VERSION 5.7 ;
BUSBITCHARS "[]" ;
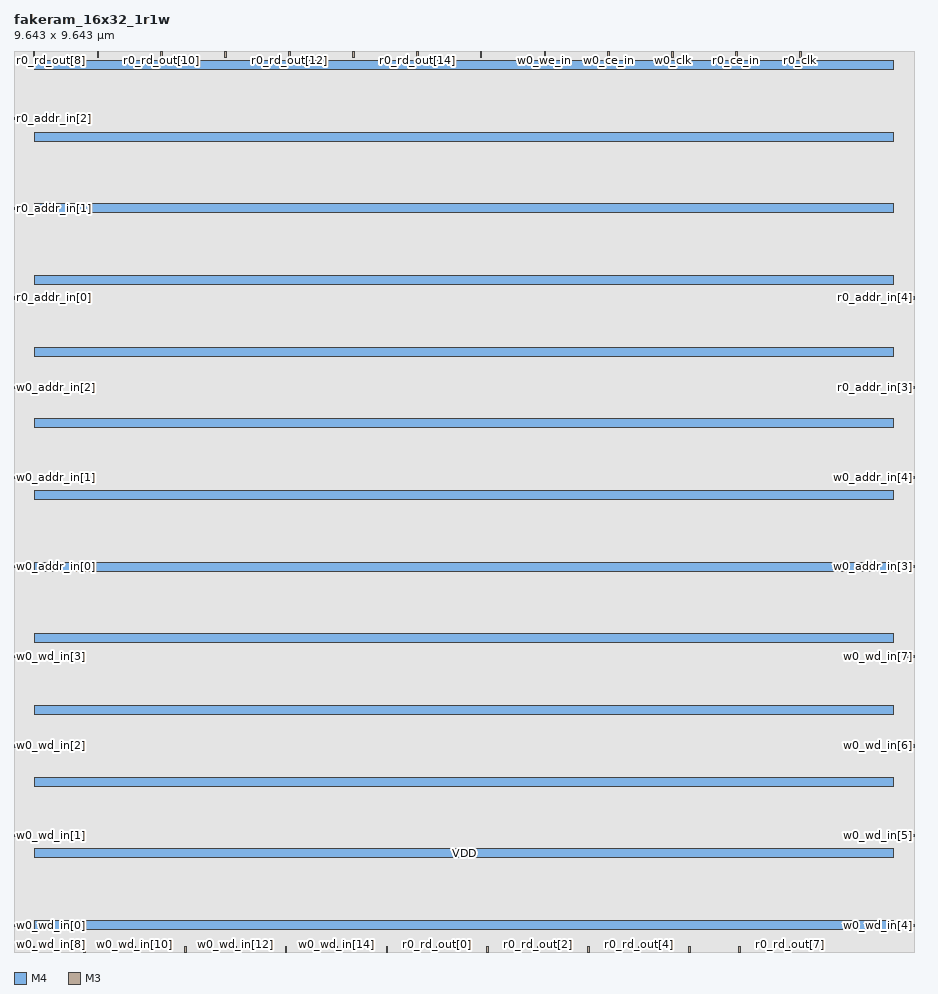
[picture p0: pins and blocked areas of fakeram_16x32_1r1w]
MACRO fakeram_16x32_1r1w
  FOREIGN fakeram_16x32_1r1w 0 0 ;
  SYMMETRY X Y R90 ;
  SIZE 9.643 BY 9.643 ;
  CLASS BLOCK ;
  PIN w0_wd_in[0]
    DIRECTION INPUT ;
    USE SIGNAL ;
    SHAPE ABUTMENT ;
    PORT
      LAYER M4 ;
      RECT 0.000 0.276 0.072 0.300 ;
    END
  END w0_wd_in[0]
  PIN w0_wd_in[1]
    DIRECTION INPUT ;
    USE SIGNAL ;
    SHAPE ABUTMENT ;
    PORT
      LAYER M4 ;
      RECT 0.000 1.236 0.072 1.260 ;
    END
  END w0_wd_in[1]
  PIN w0_wd_in[2]
    DIRECTION INPUT ;
    USE SIGNAL ;
    SHAPE ABUTMENT ;
    PORT
      LAYER M4 ;
      RECT 0.000 2.196 0.072 2.220 ;
    END
  END w0_wd_in[2]
  PIN w0_wd_in[3]
    DIRECTION INPUT ;
    USE SIGNAL ;
    SHAPE ABUTMENT ;
    PORT
      LAYER M4 ;
      RECT 0.000 3.156 0.072 3.180 ;
    END
  END w0_wd_in[3]
  PIN w0_wd_in[4]
    DIRECTION INPUT ;
    USE SIGNAL ;
    SHAPE ABUTMENT ;
    PORT
      LAYER M4 ;
      RECT 9.571 0.276 9.643 0.300 ;
    END
  END w0_wd_in[4]
  PIN w0_wd_in[5]
    DIRECTION INPUT ;
    USE SIGNAL ;
    SHAPE ABUTMENT ;
    PORT
      LAYER M4 ;
      RECT 9.571 1.236 9.643 1.260 ;
    END
  END w0_wd_in[5]
  PIN w0_wd_in[6]
    DIRECTION INPUT ;
    USE SIGNAL ;
    SHAPE ABUTMENT ;
    PORT
      LAYER M4 ;
      RECT 9.571 2.196 9.643 2.220 ;
    END
  END w0_wd_in[6]
  PIN w0_wd_in[7]
    DIRECTION INPUT ;
    USE SIGNAL ;
    SHAPE ABUTMENT ;
    PORT
      LAYER M4 ;
      RECT 9.571 3.156 9.643 3.180 ;
    END
  END w0_wd_in[7]
  PIN w0_wd_in[8]
    DIRECTION OUTPUT ;
    USE SIGNAL ;
    SHAPE ABUTMENT ;
    PORT
      LAYER M3 ;
      RECT 0.207 0.000 0.225 0.054 ;
    END
  END w0_wd_in[8]
  PIN w0_wd_in[9]
    DIRECTION OUTPUT ;
    USE SIGNAL ;
    SHAPE ABUTMENT ;
    PORT
      LAYER M3 ;
      RECT 0.747 0.000 0.765 0.054 ;
    END
  END w0_wd_in[9]
  PIN w0_wd_in[10]
    DIRECTION OUTPUT ;
    USE SIGNAL ;
    SHAPE ABUTMENT ;
    PORT
      LAYER M3 ;
      RECT 1.287 0.000 1.305 0.054 ;
    END
  END w0_wd_in[10]
  PIN w0_wd_in[11]
    DIRECTION OUTPUT ;
    USE SIGNAL ;
    SHAPE ABUTMENT ;
    PORT
      LAYER M3 ;
      RECT 1.827 0.000 1.845 0.054 ;
    END
  END w0_wd_in[11]
  PIN w0_wd_in[12]
    DIRECTION OUTPUT ;
    USE SIGNAL ;
    SHAPE ABUTMENT ;
    PORT
      LAYER M3 ;
      RECT 2.367 0.000 2.385 0.054 ;
    END
  END w0_wd_in[12]
  PIN w0_wd_in[13]
    DIRECTION OUTPUT ;
    USE SIGNAL ;
    SHAPE ABUTMENT ;
    PORT
      LAYER M3 ;
      RECT 2.907 0.000 2.925 0.054 ;
    END
  END w0_wd_in[13]
  PIN w0_wd_in[14]
    DIRECTION OUTPUT ;
    USE SIGNAL ;
    SHAPE ABUTMENT ;
    PORT
      LAYER M3 ;
      RECT 3.447 0.000 3.465 0.054 ;
    END
  END w0_wd_in[14]
  PIN w0_wd_in[15]
    DIRECTION OUTPUT ;
    USE SIGNAL ;
    SHAPE ABUTMENT ;
    PORT
      LAYER M3 ;
      RECT 3.987 0.000 4.005 0.054 ;
    END
  END w0_wd_in[15]
  PIN r0_rd_out[0]
    DIRECTION OUTPUT ;
    USE SIGNAL ;
    SHAPE ABUTMENT ;
    PORT
      LAYER M3 ;
      RECT 4.527 0.000 4.545 0.054 ;
    END
  END r0_rd_out[0]
  PIN r0_rd_out[1]
    DIRECTION OUTPUT ;
    USE SIGNAL ;
    SHAPE ABUTMENT ;
    PORT
      LAYER M3 ;
      RECT 5.067 0.000 5.085 0.054 ;
    END
  END r0_rd_out[1]
  PIN r0_rd_out[2]
    DIRECTION OUTPUT ;
    USE SIGNAL ;
    SHAPE ABUTMENT ;
    PORT
      LAYER M3 ;
      RECT 5.607 0.000 5.625 0.054 ;
    END
  END r0_rd_out[2]
  PIN r0_rd_out[3]
    DIRECTION OUTPUT ;
    USE SIGNAL ;
    SHAPE ABUTMENT ;
    PORT
      LAYER M3 ;
      RECT 6.147 0.000 6.165 0.054 ;
    END
  END r0_rd_out[3]
  PIN r0_rd_out[4]
    DIRECTION OUTPUT ;
    USE SIGNAL ;
    SHAPE ABUTMENT ;
    PORT
      LAYER M3 ;
      RECT 6.687 0.000 6.705 0.054 ;
    END
  END r0_rd_out[4]
  PIN r0_rd_out[5]
    DIRECTION OUTPUT ;
    USE SIGNAL ;
    SHAPE ABUTMENT ;
    PORT
      LAYER M3 ;
      RECT 7.227 0.000 7.245 0.054 ;
    END
  END r0_rd_out[5]
  PIN r0_rd_out[6]
    DIRECTION OUTPUT ;
    USE SIGNAL ;
    SHAPE ABUTMENT ;
    PORT
      LAYER M3 ;
      RECT 7.767 0.000 7.785 0.054 ;
    END
  END r0_rd_out[6]
  PIN r0_rd_out[7]
    DIRECTION OUTPUT ;
    USE SIGNAL ;
    SHAPE ABUTMENT ;
    PORT
      LAYER M3 ;
      RECT 8.307 0.000 8.325 0.054 ;
    END
  END r0_rd_out[7]
  PIN r0_rd_out[8]
    DIRECTION OUTPUT ;
    USE SIGNAL ;
    SHAPE ABUTMENT ;
    PORT
      LAYER M3 ;
      RECT 0.207 9.589 0.225 9.643 ;
    END
  END r0_rd_out[8]
  PIN r0_rd_out[9]
    DIRECTION OUTPUT ;
    USE SIGNAL ;
    SHAPE ABUTMENT ;
    PORT
      LAYER M3 ;
      RECT 0.891 9.589 0.909 9.643 ;
    END
  END r0_rd_out[9]
  PIN r0_rd_out[10]
    DIRECTION OUTPUT ;
    USE SIGNAL ;
    SHAPE ABUTMENT ;
    PORT
      LAYER M3 ;
      RECT 1.575 9.589 1.593 9.643 ;
    END
  END r0_rd_out[10]
  PIN r0_rd_out[11]
    DIRECTION OUTPUT ;
    USE SIGNAL ;
    SHAPE ABUTMENT ;
    PORT
      LAYER M3 ;
      RECT 2.259 9.589 2.277 9.643 ;
    END
  END r0_rd_out[11]
  PIN r0_rd_out[12]
    DIRECTION OUTPUT ;
    USE SIGNAL ;
    SHAPE ABUTMENT ;
    PORT
      LAYER M3 ;
      RECT 2.943 9.589 2.961 9.643 ;
    END
  END r0_rd_out[12]
  PIN r0_rd_out[13]
    DIRECTION OUTPUT ;
    USE SIGNAL ;
    SHAPE ABUTMENT ;
    PORT
      LAYER M3 ;
      RECT 3.627 9.589 3.645 9.643 ;
    END
  END r0_rd_out[13]
  PIN r0_rd_out[14]
    DIRECTION OUTPUT ;
    USE SIGNAL ;
    SHAPE ABUTMENT ;
    PORT
      LAYER M3 ;
      RECT 4.311 9.589 4.329 9.643 ;
    END
  END r0_rd_out[14]
  PIN r0_rd_out[15]
    DIRECTION OUTPUT ;
    USE SIGNAL ;
    SHAPE ABUTMENT ;
    PORT
      LAYER M3 ;
      RECT 4.995 9.589 5.013 9.643 ;
    END
  END r0_rd_out[15]
  PIN w0_addr_in[0]
    DIRECTION INPUT ;
    USE SIGNAL ;
    SHAPE ABUTMENT ;
    PORT
      LAYER M4 ;
      RECT 0.000 4.116 0.072 4.140 ;
    END
  END w0_addr_in[0]
  PIN w0_addr_in[1]
    DIRECTION INPUT ;
    USE SIGNAL ;
    SHAPE ABUTMENT ;
    PORT
      LAYER M4 ;
      RECT 0.000 5.076 0.072 5.100 ;
    END
  END w0_addr_in[1]
  PIN w0_addr_in[2]
    DIRECTION INPUT ;
    USE SIGNAL ;
    SHAPE ABUTMENT ;
    PORT
      LAYER M4 ;
      RECT 0.000 6.036 0.072 6.060 ;
    END
  END w0_addr_in[2]
  PIN w0_addr_in[3]
    DIRECTION INPUT ;
    USE SIGNAL ;
    SHAPE ABUTMENT ;
    PORT
      LAYER M4 ;
      RECT 9.571 4.116 9.643 4.140 ;
    END
  END w0_addr_in[3]
  PIN w0_addr_in[4]
    DIRECTION INPUT ;
    USE SIGNAL ;
    SHAPE ABUTMENT ;
    PORT
      LAYER M4 ;
      RECT 9.571 5.076 9.643 5.100 ;
    END
  END w0_addr_in[4]
  PIN r0_addr_in[0]
    DIRECTION INPUT ;
    USE SIGNAL ;
    SHAPE ABUTMENT ;
    PORT
      LAYER M4 ;
      RECT 0.000 6.996 0.072 7.020 ;
    END
  END r0_addr_in[0]
  PIN r0_addr_in[1]
    DIRECTION INPUT ;
    USE SIGNAL ;
    SHAPE ABUTMENT ;
    PORT
      LAYER M4 ;
      RECT 0.000 7.956 0.072 7.980 ;
    END
  END r0_addr_in[1]
  PIN r0_addr_in[2]
    DIRECTION INPUT ;
    USE SIGNAL ;
    SHAPE ABUTMENT ;
    PORT
      LAYER M4 ;
      RECT 0.000 8.916 0.072 8.940 ;
    END
  END r0_addr_in[2]
  PIN r0_addr_in[3]
    DIRECTION INPUT ;
    USE SIGNAL ;
    SHAPE ABUTMENT ;
    PORT
      LAYER M4 ;
      RECT 9.571 6.036 9.643 6.060 ;
    END
  END r0_addr_in[3]
  PIN r0_addr_in[4]
    DIRECTION INPUT ;
    USE SIGNAL ;
    SHAPE ABUTMENT ;
    PORT
      LAYER M4 ;
      RECT 9.571 6.996 9.643 7.020 ;
    END
  END r0_addr_in[4]
  PIN w0_we_in
    DIRECTION INPUT ;
    USE SIGNAL ;
    SHAPE ABUTMENT ;
    PORT
      LAYER M3 ;
      RECT 5.679 9.589 5.697 9.643 ;
    END
  END w0_we_in
  PIN w0_ce_in
    DIRECTION INPUT ;
    USE SIGNAL ;
    SHAPE ABUTMENT ;
    PORT
      LAYER M3 ;
      RECT 6.363 9.589 6.381 9.643 ;
    END
  END w0_ce_in
  PIN w0_clk
    DIRECTION INPUT ;
    USE SIGNAL ;
    SHAPE ABUTMENT ;
    PORT
      LAYER M3 ;
      RECT 7.047 9.589 7.065 9.643 ;
    END
  END w0_clk
  PIN r0_ce_in
    DIRECTION INPUT ;
    USE SIGNAL ;
    SHAPE ABUTMENT ;
    PORT
      LAYER M3 ;
      RECT 7.731 9.589 7.749 9.643 ;
    END
  END r0_ce_in
  PIN r0_clk
    DIRECTION INPUT ;
    USE SIGNAL ;
    SHAPE ABUTMENT ;
    PORT
      LAYER M3 ;
      RECT 8.415 9.589 8.433 9.643 ;
    END
  END r0_clk
  PIN VSS
    DIRECTION INOUT ;
    USE GROUND ;
    PORT
      LAYER M4 ;
      RECT 0.216 0.240 9.427 0.336 ;
      RECT 0.216 1.008 9.427 1.104 ;
      RECT 0.216 1.776 9.427 1.872 ;
      RECT 0.216 2.544 9.427 2.640 ;
      RECT 0.216 3.312 9.427 3.408 ;
      RECT 0.216 4.080 9.427 4.176 ;
      RECT 0.216 4.848 9.427 4.944 ;
      RECT 0.216 5.616 9.427 5.712 ;
      RECT 0.216 6.384 9.427 6.480 ;
      RECT 0.216 7.152 9.427 7.248 ;
      RECT 0.216 7.920 9.427 8.016 ;
      RECT 0.216 8.688 9.427 8.784 ;
      RECT 0.216 9.456 9.427 9.552 ;
    END
  END VSS
  PIN VDD
    DIRECTION INOUT ;
    USE POWER ;
    PORT
      LAYER M4 ;
      RECT 0.216 0.240 9.427 0.336 ;
      RECT 0.216 1.008 9.427 1.104 ;
      RECT 0.216 1.776 9.427 1.872 ;
      RECT 0.216 2.544 9.427 2.640 ;
      RECT 0.216 3.312 9.427 3.408 ;
      RECT 0.216 4.080 9.427 4.176 ;
      RECT 0.216 4.848 9.427 4.944 ;
      RECT 0.216 5.616 9.427 5.712 ;
      RECT 0.216 6.384 9.427 6.480 ;
      RECT 0.216 7.152 9.427 7.248 ;
      RECT 0.216 7.920 9.427 8.016 ;
      RECT 0.216 8.688 9.427 8.784 ;
      RECT 0.216 9.456 9.427 9.552 ;
    END
  END VDD
  OBS
    LAYER M1 ;
    RECT 0 0 9.643 9.643 ;
    LAYER M2 ;
    RECT 0 0 9.643 9.643 ;
    LAYER M3 ;
    RECT 0 0 9.643 9.643 ;
    LAYER M4 ;
    RECT 0 0 9.643 9.643 ;
  END
END fakeram_16x32_1r1w

END LIBRARY
